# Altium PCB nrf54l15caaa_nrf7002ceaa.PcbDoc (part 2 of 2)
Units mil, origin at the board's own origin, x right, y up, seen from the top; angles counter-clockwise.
Board outline 890.45 x 692.95 mil, 6 copper layers (Top Layer, Mid Layer 1, Mid Layer 2, Mid-Layer 3, Mid-Layer 4, Bottom Layer), stack 38.012 mil thick; 75 components, 69 nets, 285 pads, 346 vias.
Unrouted connection lines stored in the file: 4.

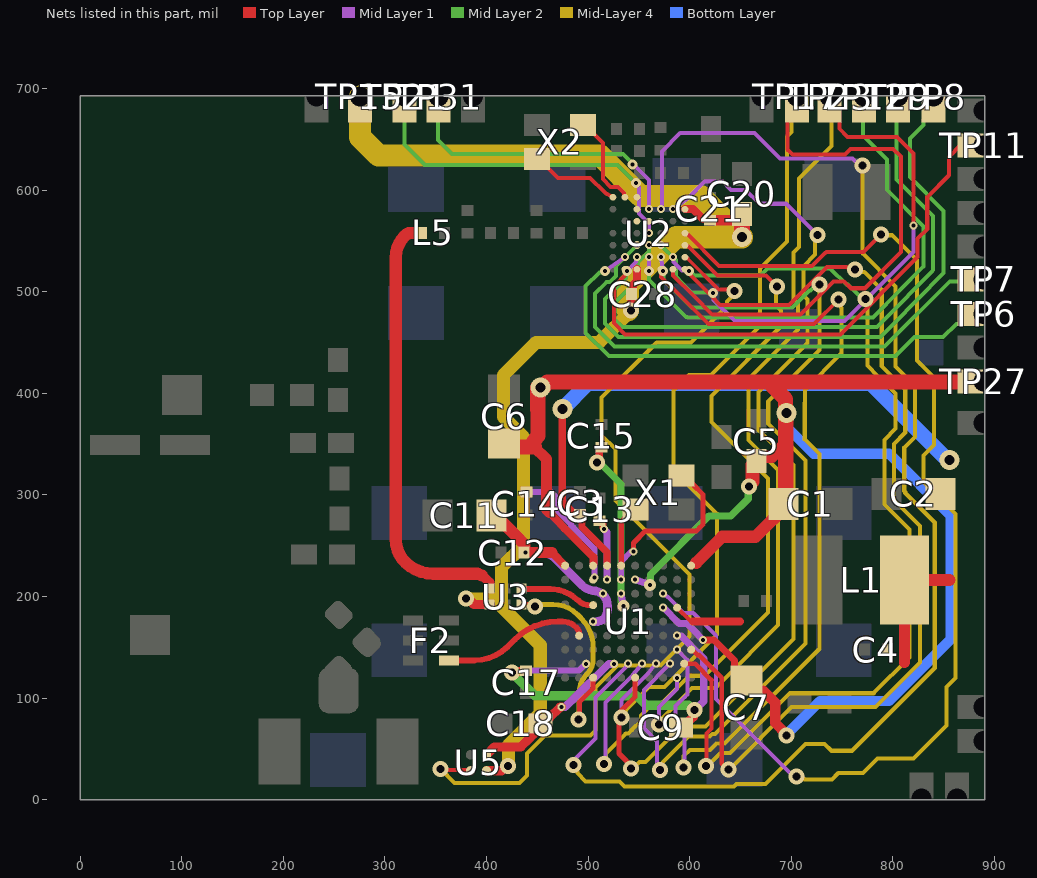
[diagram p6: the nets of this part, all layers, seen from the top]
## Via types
v1: diameter 7.87, hole 3.94, Top Layer to Mid Layer 1, tented top, 93 vias
v2: diameter 19.68, hole 9.84, Top Layer to Bottom Layer, tented both sides, 83 vias
v3: diameter 15.75, hole 7.87, Top Layer to Bottom Layer, tented both sides, 58 vias
v4: diameter 7.87, hole 3.94, Top Layer to Mid Layer 1, tented both sides, 43 vias
v5: diameter 9.84, hole 3.94, Mid Layer 1 to Mid Layer 2, tented top, 22 vias
v6: diameter 15.75, hole 7.87, Mid Layer 1 to Mid Layer 2, tented both sides, 12 vias
v7: diameter 15.75, hole 7.87, Mid Layer 2 to Mid-Layer 4, tented both sides, 11 vias
v8: diameter 11.81, hole 3.94, Top Layer to Mid Layer 1, tented top, 9 vias
v9: diameter 7.87, hole 3.94, Mid Layer 1 to Mid Layer 2, tented top, 6 vias
v10: diameter 11.81, hole 3.94, Mid Layer 1 to Mid Layer 2, 3 vias
v11: diameter 11.81, hole 3.94, Mid Layer 1 to Mid Layer 2, tented both sides, 3 vias
v12: diameter 9.84, hole 3.94, Mid Layer 1 to Mid Layer 2, 2 vias
v13: diameter 11.81, hole 3.94, Top Layer to Mid Layer 1, tented both sides, 1 vias

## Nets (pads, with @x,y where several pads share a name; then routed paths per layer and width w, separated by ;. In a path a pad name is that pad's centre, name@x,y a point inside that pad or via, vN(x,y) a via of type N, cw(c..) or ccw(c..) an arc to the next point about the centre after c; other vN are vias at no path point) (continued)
P1.06/AIN2_BUCKEN: U1.J5 U2.D7 | length 1163.9
  Top Layer w3.94: U2.D7@595.36,557.55 596.11,557.55 597.48,556.17 598.35,556.17 629.06,525.46 647.79,525.46 720.42,525.46 732.61,537.64 733.31,538.2 ccw(c725.54,552) 734.58,539 771.09,539 v3(788.32,556.23)
  Mid Layer 1 w4: v4(573.9,202.78) 574.95,202.78 578.24,199.49 578.53,199.49 594.06,183.96 603.52,183.96 626.09,161.4 626.09,99.08 702.17,23 v3(705,23)
  Mid-Layer 4 w4: v3(705,23) 707.25,20.75 712.47,20.75 713.22,20 719.37,20 ; 719.4,19.98 732.54,19.98 ; 732.57,20 739.9,20 746.24,26.34 770.49,26.34 784.81,40.66 820.29,40.66 852.73,73.1 852.73,110.99 861.73,119.99 861.73,281.14 830.23,312.64 830.23,338.66 840.68,349.11 840.68,415.41 823.73,432.36 823.73,531.18 799.31,555.6 788.95,555.6 v3(788.32,556.23)
P1.07/AIN3/STAT0: U1.B8 U2.E7 | length 827.5
  Top Layer w3.94: U2.E7@595.36,545.73 595.89,545.21 598.17,545.21 627.36,516.02 647.79,516.02 675.13,516.02 v3(686,505.15)
  Mid Layer 1 w4: v3(515.74,35.19) 516.98,36.43 516.98,95.54 543.8,122.36 544.07,122.66 552.51,132.96 v4(553.25,133.86)
  Mid-Layer 4 w4: v3(515.74,35.19) 517.48,36.93 517.48,45.5 537.12,65.14 539.68,65.14 543.42,68.87 543.47,68.87 552,77.4 552,83 564,95 573,95 600.03,122.03 614.9,122.03 676.93,184.06 676.93,315.96 621.32,371.57 621.32,397.32 690,466 690,481.38 684.8,486.59 684.8,503.95 v3(686,505.15)
P1.08_IOEN: U2.F7 U5.B2 | length 889.3
  Top Layer w3.94: U2.F7@595.82,533.4 596.63,533.4 597.09,532.94 597.62,532.94 628.41,502.15 642.88,502.15 v3(644.16,500.87)
  Top Layer w4: v3(355,30.06) 355.81,29.25 383.45,29.25 U5.B2@384.27,28.43
  Mid-Layer 4 w4: v3(355,30.06) 368.65,16.41 432.41,16.41 440,24 440,45.43 457.56,63 502.55,63 507.42,67.87 507.42,110.42 529.18,132.18 571.18,132.18 599.73,160.73 599.73,221.62 527,294.35 527,345 513.33,358.67 513.33,362.72 513.41,362.8 513.41,375.94 513.33,376.02 513.33,395.78 567.61,450.06 601.21,450.06 636.87,485.71 636.87,490.4 642.06,495.59 644.16,497.69 v3(644.16,500.87)
P1.09*: U2.B3
P1.10*: U2.C3
P1.11*: U2.C4
P1.12*: U2.A3
P1.13: TP31.1 U2.B4 | length 296.8
  Mid Layer 1 w3.94: v5(543.8,625) 544.81,625 559.93,609.89 v1(559.93,581.17)
  Mid Layer 2 w3.94: TP31.1@349.85,680.16 349.85,692.95 ; TP31.1@352.38,680.16 352.38,649.41 366.29,635.5 534.31,635.5 543.8,626.01 v5(543.8,625)
P1.14_IRQ: U1.B10 U2.B5 | length 1351.1
  Mid Layer 1 w3.94: v1(571.74,581.17) 572.63,586.51
  Mid Layer 1 w4: v5(485.73,34.18) 486.85,35.3 486.85,39.7 507.48,60.33 507.48,100.54 537.53,130.59 537.53,130.88 539.47,132.81 v4(539.47,133.86) ; 572.63,586.51 572.63,638.17 590.71,656.25 647.79,656.25 663.88,656.25 689.05,631.08 760.33,631.08 767.82,623.59 v10(769.68,623.59)
  Mid Layer 2 w3.94: v10(769.68,623.59) 770.07,623.98 v7(770.34,623.98)
  Mid-Layer 4 w3.94: v5(485.73,34.18) 485.73,30.98 489.4,27.31 489.4,26.24 497.64,18 531,18
  Mid-Layer 4 w4: 531,18 535.86,13.14 643.65,13.14 645.92,15.4 674.72,15.4 714.14,54.82 732.83,54.82 739.47,48.18 759.8,48.18 841.23,129.61 841.23,272.76 812.18,301.81 812.18,302.86 811.23,303.81 811.23,346.53 821.68,356.98 821.68,407.54 802.68,426.54 802.68,505.15 769.96,537.87 769.96,623.6 v7(770.34,623.98)
  other v7: 485.73,34.18
P1.15_SWCTRL1_STAT1: U1.A9 U2.B6 | length 928.8
  Top Layer w4.5: 536.18,91.18 536.48,91.18
  Top Layer w5: v3(542.21,30.66) 542.21,33.57 537.83,37.94 537.83,38.03 530.38,45.48 530.38,85.38 536.18,91.18 546.34,101.34 U1.A9@546.34,120.08
  Mid Layer 1 w3.94: v1@584.55,581.92 599.3,592.98
  Mid Layer 1 w4: 599.3,592.98 614.7,608.39 632.66,608.39 640.86,600.18 654.98,600.18 668.57,586.59 694.82,586.59 v3(725.64,555.77)
  Mid-Layer 4 w3.94: 556.56,37.15 563.45,44.04
  Mid-Layer 4 w4: v3(542.21,30.66) 543.94,30.66 550.42,37.15 556.56,37.15 ; 563.45,44.04 563.56,44.04 591.43,71.91 615.7,71.91 702.13,158.34 702.13,329.36 667.82,363.67 667.82,401.29 716.02,449.5 716.02,492.45 711.87,496.61 711.87,524.86 723.5,536.5 723.5,553.63 v3@727.64,557.77
  other v1: 583.55,581.17
P2.01_SCLK: U1.C1 U2.G7 | length 992.1
  Top Layer w3.94: U2.G7@595.36,522.11 595.36,521.77 607.21,509.92
  Top Layer w4: 607.21,509.92 611.18,505.96 621.55,495.59 630.08,487.06 697.81,487.06 735.23,524.48 754.57,524.48 755.13,523.92 760.54,523.92 v3(762.79,521.67)
  Top Layer w4.7: U1.C1@601.47,147.64 602.33,147.64 607.41,142.56 608.97,142.56 631.6,119.93 631.6,35.55 635.5,31.65 635.55,31.65 637.14,30.06 v4(638,30.06)
  Mid-Layer 4 w4: v7@636.73,29.92 639.09,29.92 700.35,91.18 782.73,91.18 826.81,135.26 826.81,269.21 801.23,294.8 801.23,350.3 812.18,361.25 812.18,403.6 789.03,426.75 789.03,502.24 771.84,519.42 763.42,519.42 v3@763.09,519.75
  other v5: 637.29,30.63
  other v7: 638,29.92
P2.02_MOSI: U1.B2 U2.F6 | length 960
  Top Layer w4: v4(616.52,32.88) 616.52,65.19 621.46,70.13 621.46,101.33 621.46,117.77
  Top Layer w4.7: U1.B2@594.6,133.86 605.37,133.86 621.46,117.77
  Mid Layer 1 w3.94: v1(583.55,533.92) 584.3,533.17 584.3,529.23 592.63,520.91 598.53,520.91 v5(599.3,520.14) ; v5(616.25,33.15) v4(616.52,32.88)
  Mid Layer 2 w3.94: v5(599.3,520.14) 600.88,520.14 604.98,516.04 669.78,516.04 676.74,523 738.16,523 754.16,507 755.96,507 769.97,492.99 v7(773.16,492.99) ; v7(616.3,33.06) v7(616.3,33.06)
  Mid-Layer 4 w4: v7(616.3,33.06) 617.54,33.06 630.26,45.78 631.43,45.78 639.82,45.78 698.84,104.8 781.15,104.8 816.46,140.11 816.46,265.85 791.73,290.58 791.73,354.24 802.68,365.19 802.68,399.62 785.59,416.7 ; v7(773.16,492.99) 775.14,491.02 775.14,427.21 785.59,416.75
P2.04_MISO: U1.B4 U2.F5 | length 905
  Mid Layer 1 w3.94: 554.91,101.33 554.91,107.96 v4(580.82,133.86) ; v1(571.74,533.92) v5(573.71,520.14)
  Mid Layer 1 w4: 554.91,101.33 554.91,70.52 568,57.43 568,35.75 572.3,31.44 v5(572.3,30.48)
  Mid Layer 2 w3.94: v5(572.3,30.48) 572.63,30.15 v7@572.63,29.92 ; v5(573.71,520.14) 574.44,519.41 574.44,511.67 590.53,495.59 600.68,485.43 601.84,484.28 701.11,484.28 718.06,501.23 719.04,501.23 724.8,507 v7(728,507)
  Mid-Layer 4 w4: v7@571.09,30.01 573.25,32.16 573.25,36.39 598.95,62.09 619.6,62.09 622.29,64.78 624.93,64.78 714,153.85 714,333.66 677.32,370.34 677.32,392.15 728,442.82 v7(728,507)
  other v7: 571,29
P2.05_CS: U1.C3 U2.G5 | length 894.9
  Top Layer w3.94: U2.G5@571.74,522.11 571.77,514.59 590.78,495.59 618.37,468 722.55,468 v3(746.73,492.18)
  Mid Layer 1 w3.94: v4(587.7,147.64) 597.63,137.72 597.63,103.63 595.33,101.33 586.27,92.27 586.27,76.34 594.98,67.63 v3@594.98,31.62
  Mid-Layer 4 w4: v3(594,31.62) 594.16,31.78 594.16,43.09 600.09,49.02 620.06,49.02 626.32,55.28 634.42,55.28 727.73,148.59 727.73,340.27 713.3,354.7 713.3,390.44 713.44,390.59 713.44,403.44 749.65,439.65 749.65,483.96 748.98,484.63 748.98,489.93 v3(746.73,492.18)
P2.06: TP12.1 U2.F4 | length 520.7
  Mid Layer 1 w3.94: v5(559.93,520.14) v1(559.93,533.92)
  Mid Layer 2 w3.94: v5(559.93,520.14) 559.93,511.45 575.79,495.59 575.84,495.59 596.18,475.25 597.52,475.25 597.93,474.84 645.73,474.84 ccw(c647.79,500.03) 649.86,474.84 780.58,474.84 781.75,476.02 830,525.05 830,564.35 794,600.35 794,630.34 770.46,653.88 770.46,690.98 TP12.1@771.46,691.98
P2.07: TP9.1 U2.E4 | length 613.2
  Mid Layer 2 w3.94: v1(559.93,545.73) 559.79,545.59 559.79,539.69 549.1,529 549.1,512.15 526.03,489.08 526.03,472.78 532.25,466.56 533.4,465.41 645.37,465.41 ccw(c647.79,500.03) 650.21,465.41 784.49,465.41 791.19,472.11 838.31,519.99 839.44,521.14 839.44,574.56 803.44,610.56 803.44,690.33 TP9.1@805.08,691.98
  other v9: 559.93,545.73
P2.08: TP21.1 U2.D4 | length 345.5
  Mid Layer 1 w3.94: v5(547.38,607) 547.38,605.4 549.99,602.8 549.99,577.19 559.79,567.39 559.79,557.69 v1(559.93,557.55)
  Mid Layer 2 w3.94: TP21.1@319.33,691.98 319.33,644.87 339.45,624.75 477.52,624.75 528.74,624.75 546.49,607 v5(547.38,607)
P2.09: TP8.1 U2.F3 | length 640.7
  Mid Layer 1 w3.94: v5(538.27,520.14) 547.36,529.23 547.36,533.17 v1(548.12,533.92)
  Mid Layer 2 w3.94: v5(538.27,520.14) 537.29,519.16 537.29,513.69 516.59,492.99 516.59,468.87 530.1,455.36 779.82,455.36 781.31,455.36 787.79,455.36 800.61,468.18 ; 800.63,468.21 848.87,517.23 850,518.37 850,579.58 816.89,612.69 816.89,650.89 830.16,664.16 830.16,668.35 839.44,677.63 840,677.63 TP8.1@840,691.98
P2.10: TP11.1 U2.G2 | length 544.1
  Top Layer w3.94: 525.48,495.59 525.48,505.38 536.24,516.14 U2.G2@536.31,522.11 U2.G2@536.31,522.11
  Top Layer w4: 525.48,495.59 525.48,469.01 536.49,458 748.25,458 824.39,534.14 824.39,552.35 833.86,561.82 833.86,593.26 855.22,614.62 855.22,621.02 855.28,621.08 855.28,632.72 867.27,644.71 890.45,644.71
PALDO: C11.2 C12.2 U1.E16 U1.J14 U1.L20 | length 225.8
  Top Layer w7.87: 464.47,243.3 U1.L20@477.42,230.34
  Top Layer w11: 431.7,256.75 431.7,257.04 ; C12.2@437.29,244.35 v4(438.43,243.21) ; C12.2@438.43,243.3 464.47,243.3
  Top Layer w12: C11.2@404.83,279.88 408.85,279.88 431.7,257.04 ; 431.7,256.75 437.29,251.15 C12.2@437.29,244.35
  Mid Layer 1 w8.5: v4(438.43,243.21) 438.52,243.3 454.49,243.3 cw(c454.49,225.52) 467.07,238.09 479.05,226.1 493.84,211.31 ; 493.84,211.21 ccw(c507.48,224.85) 507.48,205.57 ; v4(504.99,175.21) 506.43,175.21 ccw(c506.43,193.21) 515.1,177.43 ccw(c505.3,187.24) 519.16,187.24 519.16,190.8 ccw(c503.26,190.8) v4@514.5,202.04 ; 507.48,205.47 cw(c503.93,189.97) v4@514.5,201.84
  other v4: 514.73,202.78
PWRIOVDD: C9.1 C17.2 U1.B17 U1.D3 | length 390.9
  Top Layer w6: C17.2@438.71,127.12 C17.2@438.97,126.87
  Top Layer w9: v3(425,125) 426.05,126.05 437.64,126.05 C17.2@438.71,127.12 ; C9.1@591.42,71.18 593.39,71.18 603.71,81.49 603.71,87.21 v3(605,88.5)
  Mid Layer 1 w6: 433.39,127 491.03,127 497.22,133.18 v4@497.72,133.18
  Mid Layer 1 w7: v4(587.69,161.43) 587.86,161.26 591.67,161.26 600.85,152.08 600.85,151.94 613.91,138.88 613.91,96.91 v3@605.25,88.25
  Mid Layer 2 w9: v3(425,125) 426.44,123.58 447.74,102.28 547.82,102.28 557.1,93 598.67,93 603.17,88.5 v3(605,88.5)
  other v4: 498.08,133.54
QSPI_DIO2_P2.03: TP23.1 U1.A3 U2.E5 | length 1332.2
  Top Layer w3.94: TP23.1@737.83,679.18 TP23.1@737.83,691.98 747.26,682.55 747.26,660.4 755.39,652.27 804.24,652.27 820.28,636.23 v1@820.28,565.11
  Mid Layer 1 w4: v7(570,74) 570,91.46 587.69,109.15 v4(587.69,120) ; v5(622.95,498.66) 623.57,498.04 623.57,495.59 623.57,491.84 644.42,471 752.18,471 820.18,539 v1(820.18,565.01)
  Mid Layer 2 w3.94: v9@571.81,545.66 586.5,530.97 586.5,516.36 586.42,514.88 586.42,514.81 593.07,508.16
  Mid Layer 2 w4: 593.04,508.14 602.03,499.15 622.46,499.15 v5(622.95,498.66)
  Mid-Layer 4 w3.94: v7(570,74) 570,77.2 574.07,81.26 574.07,81.55 593.85,101.33 602.52,110 625.27,110 631.69,116.42 687,171.73 687,324.73 657.92,353.81 657.92,414.2 706.55,462.84 706.55,488.53 702.4,492.69 702.4,538.76 707.55,543.91 707.55,611.55 739.5,643.5 739.5,690.31 TP23.1@737.83,691.98
  other v1: 571.74,545.73
  other v5: 570,74
  other v9: 571.74,545.73
QSPI_DIO3_P2.00: TP17.1 U1.B6 U2.G6 | length 1356.2
  Top Layer w3.94: U2.G6@583.55,522.11 U2.G6@583.55,522.11 583.62,516.14 604.17,495.59
  Top Layer w4: 604.17,495.59 622.2,477.56 709.11,477.56 741.77,510.22 751.8,510.22 758.61,503.41 772.41,503.41 807.92,538.92 807.92,632.96 800.28,640.6 758.29,640.6 752.69,635 701.11,635 696.37,639.74 696.37,682.83 TP17.1@705.52,691.98
  Mid Layer 1 w4: v5(532.97,80.65) 532.97,98.09 558.44,123.56 v4(566.82,134.23)
  Mid Layer 2 w3.94: v5@530.12,80.65 v5(532.97,80.65)
  Mid-Layer 4 w4: v5(532.97,80.65) 532.97,83.82 537.14,88 537.14,88.09 560.04,110.99 575.16,110.99 626.96,162.79 626.96,281.07 584,324.03 584,402.72 599.18,417.89 620.89,417.89 667.59,464.59 667.59,477.59 669.28,479.28 669.28,522.66 696,549.38 696,653 700.35,657.35 700.35,686.81 TP17.1@705.52,691.98
  other v7: 532.97,81
RF: L5.2 U3.3 | length 433.1
  Top Layer w9.5: 395.57,220.68 cw(c395.57,219.02) 396.75,220.2 403,213.95 U3.3@403.3,212.6 ; U3.3@403,212.6 403.16,212.44 U3.3@403.16,212.26
  Top Layer w12: L5.2@335,557.92 326.34,557.92 ccw(c326.34,548.57) 319.73,555.18 ccw(c341.46,533.45) 310.73,533.45 310.73,256.22 ccw(c342.41,256.22) 320.01,233.82 ccw(c347.42,261.24) 347.42,222.47 391.27,222.47 395.57,220.68
RFVDD: C13.2 U1.K13 | length 59.7
  Top Layer w7: C13.2@512.44,273.58 513.03,273.58 514.84,271.76 514.84,267.4 v1(515.84,266.41)
  Mid Layer 1 w7: v1@516,266.24 516,266 518.73,263.27 v4(518.73,216.64)
SW_CTRL0: U1.A16 U3.6 | length 214.6
  Top Layer w5: U3.6@434.66,192.13 443.6,192.13 cw(c443.6,184.87) v3@448.73,190 ; v3@491.33,80.65 491.55,80.87 491.55,96.31 504.99,109.74 U1.A16@504.99,120.08
  Mid Layer 1 w5: v3@490.55,80.65 v3@491.33,80.65
  Mid-Layer 4 w5: v3@448.73,192.18 465.6,192.18 cw(c465.6,158.26) 489.58,182.25 ; 489.59,182.24 493.08,178.75 ; v3@491.21,79.95 491.21,105.32 cw(c516.68,105.32) 498.65,123.31 ccw(c483.41,138.59) 502.46,128.45 ccw(c483.41,138.59) 504.99,138.59 504.99,150 ccw(c464.33,150) 502.46,164.12 ccw(c464.33,150) 493.1,178.73
  other v3: 490.64,79.02 447.73,190
SWDCLK: TP7.1 U2.E3 | length 517.4
  Mid Layer 2 w3.94: v9(548.12,545.73) 527.45,525.07 527.45,515.66 521.11,509.32 518.13,509.32 507.03,498.21 507.03,465.09 526.19,445.93 785.71,445.93 791.7,445.93 855.99,510.22 890.45,510.22
  other v1: 548.12,545.73
SWDIO: TP6.1 U2.F2 | length 513.9
  Mid Layer 1 w3.94: v5(516.62,520.14) 536.21,533.85 v1(536.31,533.92)
  Mid Layer 2 w3.94: v5(516.62,520.14) 515.49,519.01 511.13,519.01 497.54,505.43 497.54,459.49 520.54,436.49 802.49,436.49 821.36,455.36 849.36,455.36 862.45,468.45 865.83,468.45 871.73,474.36 871.73,475.29 890.18,475.29
SXLDO: C14.2 U1.K16 | length 124.2
  Mid Layer 1 w6: v4(439.16,302.74) 463.38,302.74 467.48,298.64 ; 467.48,287.08 483.33,271.22 483.33,269.88 485.56,267.65 506.22,247 v4@506.22,220.48 ; 467.58,287.08 467.58,298.64
  other v4: 506.43,218.5
TXRF0: U1.G16 U3.1 | length 74.7
  Top Layer w5.75: 466.89,207.08 cw(c463.01,170.65) 475.42,205.12 cw(c463.01,170.65) 478.7,203.76 482.1,202.14 cw(c477.42,192.26) 484.12,200.9 ; 484.16,200.88 490.52,195.94 ccw(c501.31,206.72) 493.54,193.6 ccw(c501.31,206.72) 497.91,191.86 ccw(c501.31,206.72) 501.31,191.47 U1.G16@504.99,191.47
  Top Layer w5.76: U3.1@434.66,207.87 435.07,207.46 463.14,207.46 466.89,207.08
TXRF1: F2.1 U1.D18 | length 148.8
  Top Layer w5.76: F2.1@360.42,137.4 F2.1@363.03,137.4 ; F2.1@363.03,137.18 388.08,137.18 ccw(c388.08,183.75) 421.01,150.82 428.02,157.83 cw(c470.36,115.49) 470.36,175.37 474.64,175.37 cw(c474.6,156.17) 488.18,169.75 488.55,169.37 ; 488.57,169.35 cw(c481.57,162.39) U1.D18@491.44,162.39
VBAT: C1.2 C5.1 C6.2 C7.2 TP27.1 U1.F5 U1.K9 U1.L1 U1.L16 | length 1860.4
  Top Layer w7: v1(613.29,157.09) 623.98,157.09 643.99,137.07 643.99,127.12 C7.2@649.72,121.39
  Top Layer w7.87: 461.95,282.79 476.26,267.65 ; 477.24,266.66 505.19,238.72 U1.L16@505.19,232.06
  Top Layer w10: C7.2@652.69,122.44 656.21,118.92 656.21,116.87 665.44,107.64 672.03,107.64 684.24,95.43 684.24,75.48 695.15,64.56 v3(695.15,63.01)
  Top Layer w11: 446.95,347.25 458.94,335.26 458.94,290.34 458.94,285.97 461.95,282.79
  Top Layer w12: 606.48,233.17 632.14,258.83 664.84,258.83 C1.2@681.99,275.98 ; v3(658.15,308.43) 658.15,309.45 v3@661.8,313.1 ; C5.1@661.8,329.33 C5.1@665.64,333.17 ; C5.1@667.99,337.48 680.92,337.48 694.5,351.06
  Top Layer w12.5: C1.2@681.97,275.98 C1.2@691.24,284.24
  Top Layer w14: v3@661.8,313.1 C5.1@661.8,329.33
  Top Layer w15: C6.2@417.43,345.61 419.07,347.25 446.95,347.25 ; 445.18,350.18 450.59,358.26 ; v2@450.58,405.68 450.77,358.26 ; v2(453.03,405.69) 454.3,405.69 459.8,411.18 677.33,411.18 694.26,394.25 v2@694.26,381.47 ; v2@453.93,406.58 v2@457.24,406.58 ; 660,411.18 TP27.1@886.57,411.18 ; C1.2@692.24,291.22 694.5,293.49 694.5,351.06 v2@694.5,379.92
  Mid Layer 1 w6.8: v4@574.18,188.99 589.71,173.46 597.19,173.46 603.22,167.43 ; 603.22,167.39 613.29,157.32 v1(613.29,157.09)
  Mid Layer 1 w7: v4@547.38,216.2 v11(561.01,211.47)
  Mid Layer 2 w7: v11(561.01,211.47) 561.37,211.83 561.37,221.82 618.96,279.41 640.77,279.41 657.61,296.25 v3@657.61,307.39
  Bottom Layer w10: v3(695.15,63.01) 695.15,64.06 728.12,97.03 796.1,97.03 856.59,157.52 856.59,280.14 796.28,340.45 721.91,340.45 696.04,366.32 v2@696.04,379.69
  other v2: 695.15,380.57
  other v4: 573.9,188.99 546.34,216.56
VDD_BUCK: C2.2 C3.2 C4.2 L1.2 U1.F3 U1.L13 | length 785.3
  Top Layer w4.2: U1.F3@587.69,188.99 600.27,176.41 602.32,176.41
  Top Layer w7: v2(474.64,384.48) 474.64,293.5 486.44,281.7 490.24,281.7 C3.2@492.06,279.88 ; C3.2@494.07,278.15 494.07,268.23 518.77,243.53 U1.L13@518.77,230.34
  Top Layer w8: 603.34,175.39 649.39,175.39
  Top Layer w10.98: 811.52,134.92 L1.2@811.52,211.97
  Top Layer w12: L1.2@808.74,216.22 L1.2@811.52,216.22 855.83,216.22
  Bottom Layer w15: v2(474.64,384.48) 500.16,410 778.15,410 851.34,336.81 852.32,336.81 854.66,334.47 v2(855.93,334.47)
VDD_nRF: C20.2 C21.1 C28.1 TP15.1 U2.B7 U2.G3 U3.4 U5.A2 | length 1387.6
  Top Layer w7.87: v3(542.25,481.36) 542.53,481.64 542.53,497.23 C28.1@542.8,497.51 ; C28.1@544.18,497.51 544.18,506.67 548.12,510.61 U2.G3@548.12,522.11 ; U2.B7@595.36,581.54 603.23,581.54 613.08,571.7 C21.1@618.59,571.7
  Top Layer w9: v3(380,198) 381.83,198 387.7,192.13 U3.4@403.16,192.13 ; U5.A2@400.02,28.43 400.07,28.48 414.74,28.48
  Top Layer w10.63: C21.1@619.97,570.32 C20.2@645.16,570.32
  Top Layer w15.75: v2(651.46,553.99) C20.2@651.46,576.62
  Mid-Layer 4 w10: v3@381.1,198.9 414.77,198.9
  Mid-Layer 4 w13: v3(421.14,33.06) 421.67,33.58 421.67,53.67 453.03,85.04 453.03,151.96 414.77,190.23 414.77,198.9 414.77,228.78 436.52,250.52 436.52,356.92 416.73,376.71 416.73,417.89 448.9,450.06 510.94,450.06 v3(542.25,481.36)
  Mid-Layer 4 w15: 275.46,656.52 275.61,656.38 275.61,652.14
  Mid-Layer 4 w22: 275.46,656.52 TP15.1@275.46,691.98 ; 275.61,652.14 293.75,634 511.98,634 551.8,594.18 610.89,594.18 651.46,553.61 586.71,553.61 539,505.9 v3@539,481.71
VDDIO: C18.2 U1.B12 U5.A1 | length 157.2
  Top Layer w7.87: U5.A1@400.02,44.18 U5.A1@400.28,44.44
  Top Layer w9: U5.A1@400.13,44.23 407.91,52 433.79,52 442.34,60.55 446.1,64.32 446.1,69.84 451.45,75.18 C18.2@453.41,75.18 ; C18.2@460.35,80.53 461.92,80.53 472.58,91.18 v1(473.9,91.18)
  Mid Layer 1 w7.87: v1(473.9,91.18) 477.39,91.18 483.87,97.66 484.3,97.66 520.42,133.79 v4(525.68,133.79)
XC1: U2.A1 X2.1 | length 89.8
  Top Layer w3.94: X2.1@449.69,630.76 458.55,621.9 460.55,621.9 470.3,612.15 502.09,612.15 515.99,598.25 516.6,597.63 ccw(c522.17,603.2) 518.42,596.28 522.41,594.11 U2.A1@524.49,592.98
XC2: U2.A2 X2.3 | length 91.4
  Top Layer w3.94: X2.3@494.97,664.22 X2.3@503.83,655.36 ; X2.3@505.79,655.36 514.65,646.5 514.65,610.72 522.17,603.2 529.42,603.2 535.55,597.06 535.55,594.11 U2.A2@536.31,593.36
XOLDO: C15.2 U1.J11 | length 180
  Top Layer w7.5: v3@508.94,331 508.94,333.23 510.87,335.17 510.87,345.36 512.44,346.93 C15.2@513.03,346.93
  Mid Layer 1 w7: v4(532.56,202.78) v11(534.76,190.57)
  Mid Layer 2 w7: v3@512.15,330.83 532.34,310.64 532.34,194.15 534.76,191.73 v11(534.76,190.57)
  other v3: 508.94,331.8
XON: U1.L11 X1.1 | length 60.3
  Top Layer w5.5: U1.L11@532.56,230.34 532.56,273.46 X1.1@544.69,285.59
XOP: U1.K11 X1.3 | length 177.1
  Top Layer w5: v4(544.71,244.2) 544.71,252.75 556.55,264.6 606.78,264.6 609.83,267.65 613.29,271.11 613.29,300.24 602.8,310.73 600.26,310.73 X1.3@591.93,319.06
  Mid Layer 1 w5.5: v4(532.65,216.62) 532.65,234.72 541.87,243.94 544.45,243.94 v4(544.71,244.2)
pads on no net: A1.1 A1.2 A1.3 U1.C20 U1.K5 U1.K7 U1.L5 U1.L7

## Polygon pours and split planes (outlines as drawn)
GND on Top Layer "g0.01" (solid, remove dead copper, pour order 1145): -46.27,730.33 909.73,730.33 909.73,421.38 378.26,421.38 378.26,-14.82 -46.27,-14.82
GND on Top Layer "Top_Layer-GND" (solid, remove dead copper, pour order 1024): 361.18,-14.82 361.18,432.45 890.53,432.45 890.53,-14.82
VDD_BUCK on Top Layer "NONET_L-01_P-001" (solid, pour order 1148): 869.18,346.41 877.47,338.12 877.47,138.48 852.45,113.46 700.77,113.46 645.71,168.52 627.85,168.52 624.54,171.82 624.54,182.98 653.14,183.08 704.05,132.18 779.54,132.18 787.31,139.95 787.31,258.46 813.32,284.47 813.32,336.12 823.61,346.41
GND on Top Layer "NONET_L-01_P-001" (solid, pour order 1150): 667.38,202.89 661.09,209.18 594.34,209.18 594.34,226.01 691.53,226.01 693.85,223.69 693.85,168.18 695.51,166.52 755.83,166.52 758.97,169.74 758.97,263.4 755.48,266.89 733.5,266.89 725.54,274.84 725.54,302.65 769.24,346.34 816.46,346.34 820.64,342.17 820.64,279.54 807.98,266.89 784.28,266.89 779.16,261.77 779.16,173.37 782.43,170.1 782.43,141.97 778.15,137.8 704.97,137.8 667.38,175.39
GND on Mid Layer 1 "Mid_Layer_1-GND" (solid, remove dead copper, pour order 1149): -6.8,733.45 -6.8,-28.82 919.65,-28.82 919.65,733.45
GND on Mid Layer 1 "GND_L02_P1032" (solid, pour order 1032): 647.41,225.39 647.57,164.61 694.37,117.8 847.54,117.8 858.69,128.95 858.69,307.22 819.11,346.8 741.82,346.8 647.41,252.39
GND on Mid Layer 2 "Mid_Layer_2-GND" (solid, remove dead copper, pour order 1151): -3.04,732.18 -3.04,-25.82 921.96,-25.82 921.96,732.18
GND on Mid-Layer 3 "Mid_Layer_3-GND" (solid, remove dead copper, pour order 1004): -12.27,737.54 -12.27,-25.82 912.73,-25.82 912.73,737.54
GND on Mid-Layer 4 "Mid_Layer_4-GND" (solid, remove dead copper, pour order 1002): -9.09,736.28 -9.09,-12.82 924.73,-12.82 924.73,736.28
GND on Bottom Layer "Bottom_Layer-GND" (solid, remove dead copper, pour order 1001): -45.43,743.3 -45.43,-20.82 897.02,-20.82 897.02,743.3

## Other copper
Top Layer:
  rectangle net GND: 846,374 867,379.81
  rectangle net NetZ1_1: 206.48,383.7 229.98,412.7
  rectangle net NetZ2_1: 241.33,206.42 270.33,288.46
  rectangle net NetZ1_1: 241.33,304.21 270.33,370.26
  rectangle net VBAT: 672.14,326.18 691.24,337.03
  rectangle net NetA1_4: 80.54,377.88 196.83,418.04
  rectangle net GND: 556.34,172.26 563.93,206.12
  rectangle net GND: 501.25,157.63 520.1,165.2
  rectangle net GND: 514.94,143.9 550.28,192.8
  rectangle net GND: 555.61,143.9 577.6,179
  region net GND: 323.3,268.7 323.3,257.13 ccw(c341.02,257.13) 328.49,244.6 338.43,244.6 338.5,244.67 338.63,244.67 338.63,315.52 324.3,315.52 323.4,315.5 323.3,315.4
  pour cut-out: 231.6,140.28 cw(c236.41,135.47) 236.41,142.26 274.31,142.26 cw(c274.27,132.86) 280.95,139.48 cw(c269.7,128.28) 285.57,128.28 285.57,87 cw(c279.89,86.92) 283.95,82.94 cw(c280.44,85.83) 283.65,82.61 cw(c268.92,97.33) 268.92,76.51 239.55,76.51 cw(c239.55,87.37) 231.86,79.69 229.25,82.31 cw(c243.01,96.07) 223.55,96.07 223.55,126.95 cw(c238.48,126.95) 227.92,137.51 228.38,137.97 cw(c236.92,129.44)
  region net NetZ1_1: 228.12,412.7 248.21,412.7 cw(c248.22,386.61) 266.66,405.06 cw(c257.9,396.28) 270.31,396.29 270.31,377.43 270.32,370.05 241.33,370.05 241.33,378.56 ccw(c236.01,378.57) 239.77,382.33 ccw(c236.46,379.03) 236.46,383.7 228.12,383.7
  pour cut-out: 616.97,226.87 612.73,222.63 cw(c607.88,227.48) 607.88,220.62 605.41,220.62 605.27,220.76 605.27,222.47 606.98,222.47 ccw(c606.98,234.86) 616.54,226.97
  pour cut-out: 486.69,298.01 497.96,298.01 cw(c497.96,295.03) 500.07,297.14 505.53,291.67 517.34,291.67 517.34,279.86 505.53,279.86 486.69,279.88
  pour cut-out: 379,145 399.91,145 425.76,170.85 438,170.85 438,185.06 423.85,185.06 408.16,169.37 379,169.37
  pour cut-out: 779.1,427.5 835.6,427.5 835.6,421.7 835,421.1 834.4,421.7 778,421.7 778,427.5
  pour cut-out: 439.5,420.8 506.43,420.8 506.43,428.5 442.6,428.5 442.6,424.1 439.5,421
  pour cut-out: 347.33,110.55 415.36,110.55 418.91,114.1 418.91,208.4 415.33,211.97 347.33,211.97
  pour cut-out: 513.67,680.95 429.74,680.95 429.74,614.03 513.67,614.02
  pour cut-out: 204,701.99 405.71,701.99 405.71,654.99 204,654.99
  pour cut-out: 236.06,181.65 278.76,181.52 278.76,139.43 236.06,139.09
  pour cut-out: 408.48,234.01 408,233.53 408,224.08 465.33,224.08 465.33,234.28 408.42,234.28
  pour cut-out: 699.58,636.31 809.02,636.31 809.02,561.18 699.58,561.18
  pour cut-out: 853,352.18 853,704.18 895,704.18 895,352.18
  pour cut-out: 652.69,701.99 898.05,701.99 898.05,659.3 652.69,659.3
  pour cut-out: 536.31,557.55 515.74,557.55 515.74,581.17 536.31,581.17
  pour cut-out: 655.48,524.66 655.28,524.66 655.28,540.16 641.78,540.16 641.08,540.86 641.08,529.46 650.08,529.46 655.18,524.36
  pour cut-out: 4.58,729.96 204.23,729.96 204.23,-21.24 4.58,-21.24
  region net NetF2_6: 319.32,161.6 283.18,169.44 283.18,140.31 319.45,152.11
  pour cut-out: 236.33,305.44 275.41,305.33 275.41,288.91 236.33,288.61
  pour cut-out: 638.94,102.64 638.94,79.02 670.44,79.02 670.44,102.64
  pour cut-out: 691.58,225.98 693.88,223.68 693.78,223.58 693.78,168.18 693.88,168.18 695.58,166.48 695.68,166.58 755.82,166.58 758.98,169.75 758.98,263.38 758.88,263.38 755.38,266.88 731.28,266.88 731.18,266.78 731.18,259.92 750.3,259.92 750.3,172.52 701.87,172.52 701.87,232.11 628.08,232.11 628.08,226.08 630.97,226.08 631.07,225.98
  pour cut-out: 667.38,188.32 654.63,188.32 654.63,180.46 702.91,132.18 779.54,132.18 788,140.64 788,259.43 789.01,260.44 814.08,260.31 831.99,278.22 831.99,342.34 813.6,360.73 755.79,360.73 707,311.94 707,294.57 663.58,251.15 650.75,251.15 649.97,250.37 649.97,248.63 650.88,247.72 696.9,247.72 717.33,247.72 727.5,257.89 733.98,257.89 733.98,266.41 726.62,273.77 726.62,303.72 769.31,346.41 816.39,346.41 820.18,342.63 820.18,279.08 807.99,266.89 782.42,266.89 779.16,263.63 779.16,173.37 781.45,171.08 781.45,143.1 777.05,138.7 704.83,138.7 667.38,176.15
  pour cut-out: 598.18,215.18 598.18,218.84 599.54,220.2 605.52,220.2 606.78,221.46 606.78,223.8 592.41,223.8 591.81,223.21 591.81,215.23 597.73,215.23
  region net BUCKOUT: 636.53,246.18 648.64,246.18 651.01,243.81 651.01,233.85 649.34,232.18 627.71,232.18 627.44,232.45 627.44,237.11
  pour cut-out: 517.34,298.39 517.34,291.67 520.37,291.67 520.1,291.94 520.1,298.39
  pour cut-out: 869.18,346.41 877.47,338.12 877.47,138.58 852.42,113.54 700.84,113.54 700.77,113.46 645.71,168.52 621.5,168.52 617.5,164.52 619.46,162.56 619.46,156.04 643.12,156.04 699.66,99.5 862.76,99.5 890.53,127.27 890.53,353.42 883.22,360.73 811.52,360.73 811.52,346.41
  region net VBAT: 599.32,235.99 597.64,234.31 597.64,228.61 599.68,226.57 608.32,226.57 611.79,230.04 603.33,238.5 600.83,235.99
  pour cut-out: 557.34,244.2 571.35,258.21 614.68,258.21 615.3,258.83 617.5,256.63 589.39,228.52 557.34,228.52
  pour cut-out: 524.49,367.77 524.49,272.08 609.7,272.08 609.7,368.2
  pour cut-out: 613.89,226.01 613.89,234.09 630.8,251 654.54,251 656.44,249.11 655.01,247.67 637.21,247.67 631.07,241.53 631.07,226.01
  pour cut-out: 662.52,182.68 667.38,187.54 667.38,202.87 661.07,209.23 596.97,209.23 596.97,185.65 598.25,185.65 601.22,182.68
  pour cut-out: 810.63,359.73 845.31,359.73 851.87,353.17 827.27,328.57 824.34,328.57 824.34,340.4 810.63,355.14
  pour cut-out: 667.38,188.32 654.63,188.32 654.63,180.46 702.91,132.18 779.54,132.18 788,140.64 788,259.43 789.01,260.44 814.08,260.31 831.99,278.22 831.99,342.34 813.6,360.73 755.79,360.73 707,311.94 707,294.57 663.58,251.15 650.75,251.15 649.97,250.37 649.97,248.63 650.88,247.72 696.9,247.72 717.33,247.72 727.5,257.89 733.98,257.89 733.98,266.41 726.62,273.77 726.62,303.72 769.31,346.41 816.39,346.41 820.18,342.63 820.18,279.08 807.99,266.89 782.42,266.89 779.16,263.63 779.16,173.37 781.45,171.08 781.45,143.1 777.05,138.7 704.83,138.7 667.38,176.15
  pour cut-out: 829.53,285.08 845.69,268.92 819.64,268.92 819.64,275.2
  pour cut-out: 440.74,388.58 440.74,364.96 393.52,364.96 393.52,388.58
  pour cut-out: 438.6,196.63 464.37,196.63 464.37,186.87 455.49,177.99 438.41,177.99
  pour cut-out: 411.65,154.82 414.5,157.79 470.17,157.79 476.64,151.32 476.64,128.87 505.09,100.41 505.09,71.81 459.43,71.81 411.65,119.59
  pour cut-out: 366.45,303.93 390.07,303.93 390.07,256.13 366.45,256.13
Mid Layer 1:
  pour cut-out: 349.99,234.77 cw(c349.89,267.03) 327.15,244.14 cw(c337.66,252.87) 325.27,247.12 cw(c330.74,252.6) 323.3,250.46 323.3,531.42 cw(c337.41,534.35) 327.22,544.54 cw(c330.11,541.65) 330.11,545.73 351.4,545.73 351.4,569.73 323,569.73 ccw(c322.99,555.87) 313.19,565.67 307.52,560 ccw(c328.7,538.81) 302.52,553.38 ccw(c313.43,542.47) 298,542.47 298,256 ccw(c341.45,256) 310.73,225.27 313,223 ccw(c344.38,254.38) 344.38,210 356.74,210 387.56,210 cw(c387.57,198.08) 396,206.5 cw(c390.01,200.51) 398.1,203.02 399.16,202.04 407.23,202.04 ccw(c407.23,204.55) 409,202.78 410.78,204.56 ccw(c409.48,205.88) 411.33,205.89 ccw(c405.27,208.8) 411.95,208.01 ccw(c385.46,208.08) 404.22,226.78 399,232 ccw(c392.32,225.33) 392.32,234.77
  pour cut-out: 230.41,140.39 cw(c235.22,135.59) 235.22,142.38 273.12,142.38 cw(c273.08,132.97) 279.76,139.6 cw(c268.5,128.4) 284.38,128.4 284.38,87.1 cw(c278.69,87.03) 282.76,83.06 cw(c279.1,86.08) 282.46,82.72 cw(c267.73,97.45) 267.73,76.62 238.36,76.62 cw(c238.36,87.49) 230.67,79.81 228.06,82.42 cw(c241.82,96.19) 222.36,96.19 222.36,127.07 cw(c237.29,127.07) 226.73,137.62 227.19,138.09 cw(c235.73,129.56)
  pour cut-out: 222.7,418.18 222.73,422.98 258.73,422.98 cw(c258.71,404.89) 271.52,417.66 cw(c268.93,411.42) 273.73,416.18 cw(c273.24,415.66) 273.78,416.13 cw(c265.01,407.47) 277.33,407.39 277.33,175.21 232.93,175.21 232.93,370.46 ccw(c227.82,370.46) 231.43,374.08 ccw(c226.36,369.02) 226.36,376.18 222.7,376.18
  pour cut-out: 573.8,227.44 cw(c567.18,234.04) 567.16,224.69 564.64,224.69 560.86,224.69 ccw(c560.85,219.49) 557.37,223.36 556.87,222.86 ccw(c563.37,216.39) 554.2,216.33 554.2,209.66 554.17,209.63 576.19,209.63 576.19,219.03 624.06,266.42 661.44,266.42 741.82,346.8 819.18,346.8 858.69,307.29 858.69,128.49 848,117.8 695.03,117.8 631.33,181.5 620.84,171.01 686.27,105.58 856.36,105.58 873.18,122.41 873.18,339.18 854.84,357.53 735.37,357.53 656.24,278.4 624.76,278.4
  pour cut-out: 553,588.43 523,588.43 523,577.19 540.06,577.19 542.25,575 542.25,565.01 553,565.01
  region net GND: 856,358 844,358 839.89,362.11 840,373 843,376 864,376 882,358 882,343 879,340 874,340
  pour cut-out: 205,701.99 405.71,701.99 405.71,654.99 205,654.99
  pour cut-out: 848,347.18 848,702.18 895,702.18 895,347.18
  pour cut-out: 652.69,701.99 898.05,701.99 898.05,654.99 652.69,654.99
  pour cut-out: 310.11,135.18 233.35,135.18 233.35,177.31 310.11,177.31
  pour cut-out: 278.33,180.58 278.33,172.18 278.13,171.98 278.33,171.78 287.13,171.78
  pour cut-out: 288.78,135.58 280.38,135.58 280.18,135.78 279.98,135.58 279.98,126.78
  pour cut-out: 195.82,418.18 277,418.18 277,376.18 195.82,376.18
  region net BUCKOUT: 584.07,225.93 589.57,225.93 593.01,229.37 593.01,235.28 596.64,238.91 606.64,238.91 609.06,236.49 609.06,232.46 589.4,212.8 584.84,212.8 582.83,214.81 582.83,224.69
  pour cut-out: 635.93,125.54 633.37,122.98 629.24,122.98 628.11,124.12 628.11,160.22 596.01,192.32 596.01,195.51 595.94,195.8 606.21,206.07 624.56,206.07 628.11,202.52 628.11,184.17 704.66,107.62 704.66,104.68 700.39,100.41 675.16,100.41 650.04,125.54
Mid Layer 2:
  region net GND: 844,353 ccw(c845.93,354.93) 845.93,352.2 861.93,352.2 cw(c862.1,340.86) 870,349 870.59,348.41 cw(c864.18,342) 873.24,342 881.9,342 ccw(c880.69,343.21) 882.4,343.21 882.4,352.68 ccw(c870.75,352.68) 878.99,360.91 875.1,364.8 ccw(c870.75,360.46) 870.75,366.6 843,366.6 843,355.41 ccw(c846.42,355.41)
  pour cut-out: 230.41,140.39 cw(c235.22,135.59) 235.22,142.38 273.12,142.38 cw(c273.08,132.97) 279.76,139.6 cw(c268.5,128.4) 284.38,128.4 284.38,87.1 cw(c278.69,87.03) 282.76,83.06 cw(c279.1,86.08) 282.46,82.72 cw(c267.73,97.45) 267.73,76.62 238.36,76.62 cw(c238.36,87.49) 230.67,79.81 228.06,82.42 cw(c241.82,96.19) 222.36,96.19 222.36,127.07 cw(c237.29,127.07) 226.73,137.62 227.19,138.09 cw(c235.73,129.56)
  pour cut-out: 222.7,418.18 222.73,422.98 258.73,422.98 cw(c258.71,404.89) 271.52,417.66 cw(c268.93,411.41) 273.73,416.18 cw(c273.11,415.52) 273.78,416.13 cw(c265.01,407.47) 277.33,407.39 277.33,176.18 232.93,176.18 232.93,370.46 ccw(c227.82,370.46) 231.43,374.08 ccw(c226.36,369.02) 226.36,376.18 222.7,376.18
  pour cut-out: 579.61,589.27 523,589.28 523,577.46 539.36,577.46 542.25,574.57 542.25,565.01 579.61,565.01
  pour cut-out: 848,346.18 848,702.18 895,702.18 895,346.18
  pour cut-out: 652.69,701.99 898.05,701.99 898.05,654.99 652.69,654.99
  pour cut-out: 201,701.99 405.71,701.99 405.71,654.99 201,654.99
  pour cut-out: 285.73,134.68 277.33,134.68 277.13,134.88 276.93,134.68 276.93,125.88
  pour cut-out: 277.43,183.98 277.43,175.58 277.23,175.38 277.43,175.18 286.23,175.18
  pour cut-out: 308.15,135.31 233.29,135.31 233.29,177.43 308.15,177.43
  pour cut-out: 195.82,418.18 278.73,418.18 278.73,374.18 195.82,374.18
  pour cut-out: 646.91,266.42 726.83,346.34 811.99,346.34 823.98,334.35 823.98,191.42 770.36,137.8 667.18,137.8 667.18,129.92 778.13,129.92 833.59,185.39 833.59,344.45 823.48,354.56 721.11,354.56 642.07,275.51 606.3,275.51 606.3,266.42
Mid-Layer 3:
  pour cut-out: 230.41,140.39 cw(c235.22,135.59) 235.22,142.38 273.12,142.38 cw(c273.08,132.97) 279.76,139.6 cw(c268.5,128.4) 284.38,128.4 284.38,87.1 cw(c278.69,87.03) 282.76,83.06 cw(c279.1,86.08) 282.46,82.72 cw(c267.73,97.45) 267.73,76.62 238.36,76.62 cw(c238.36,87.49) 230.67,79.81 228.06,82.42 cw(c241.82,96.19) 222.36,96.19 222.36,127.07 cw(c237.29,127.07) 226.73,137.62 227.19,138.09 cw(c235.73,129.56)
  pour cut-out: 222.7,418.18 222.73,422.98 258.73,422.98 cw(c258.71,404.89) 271.52,417.66 cw(c268.93,411.42) 273.73,416.18 cw(c273.24,415.66) 273.78,416.13 cw(c265.01,407.47) 277.33,407.39 277.33,172.26 232.93,172.26 232.93,370.46 ccw(c227.82,370.46) 231.43,374.08 ccw(c226.36,369.02) 226.36,376.18 222.7,376.18
  pour cut-out: 848,347.18 848,702.18 895,702.18 895,347.18
  pour cut-out: 652.69,701.99 898.05,701.99 898.05,654.99 652.69,654.99
  pour cut-out: 202,701.99 405.71,701.99 405.71,654.99 202,654.99
  pour cut-out: 288.53,135.58 280.13,135.58 279.93,135.78 279.73,135.58 279.73,126.78
  pour cut-out: 278.73,180.38 278.73,171.98 278.53,171.78 278.73,171.58 287.53,171.58
  pour cut-out: 296.33,135.18 233.13,135.18 233.13,177.31 296.33,177.31
  pour cut-out: 195.82,418.18 278.73,418.18 278.73,376.18 195.82,376.18
Mid-Layer 4:
  pour cut-out: 222.7,416.39 222.73,421.19 258.73,421.19 cw(c258.71,403.09) 271.52,415.87 cw(c268.93,409.62) 273.73,414.38 cw(c273.11,413.73) 273.78,414.33 cw(c265.01,405.68) 277.33,405.59 277.33,173.42 232.93,173.42 232.93,368.66 ccw(c227.82,368.67) 231.43,372.29 ccw(c226.36,367.22) 226.36,374.39 222.7,374.39
  pour cut-out: 230.41,140.39 cw(c235.22,135.59) 235.22,142.38 273.12,142.38 cw(c273.08,132.97) 279.76,139.6 cw(c268.5,128.4) 284.38,128.4 284.38,87.1 cw(c278.69,87.03) 282.76,83.06 cw(c279.1,86.08) 282.46,82.72 cw(c267.73,97.45) 267.73,76.62 238.36,76.62 cw(c238.36,87.49) 230.67,79.81 228.06,82.42 cw(c241.82,96.19) 222.36,96.19 222.36,127.07 cw(c237.29,127.07) 226.73,137.62 227.19,138.09 cw(c235.73,129.56)
  pour cut-out: 848,347.18 848,702.18 895,702.18 895,347.18
  pour cut-out: 202,701.99 405.71,701.99 405.71,654.99 202,654.99
  pour cut-out: 653.02,701.99 898.05,701.99 898.05,654.99 653.02,654.99
  pour cut-out: 289.61,135.58 281.21,135.58 281.01,135.78 280.81,135.58 280.81,126.78
  pour cut-out: 278.73,180.66 278.73,172.26 278.53,172.06 278.73,171.86 287.53,171.86
  pour cut-out: 295.99,134.62 232.78,134.62 232.78,176.75 295.99,176.75
  pour cut-out: 195.82,418.18 278.73,418.18 278.73,376.18 195.82,376.18
Bottom Layer:
  pour cut-out: 205,701.99 405.71,701.99 405.71,654.99 205,654.99
  pour cut-out: 653.02,701.99 898.05,701.99 898.05,654.99 653.02,654.99
  pour cut-out: 848,347.18 848,702.18 895,702.18 895,347.18
Multi-Layer:
  pour cut-out: 175.73,-28.82 175.73,79.02 206.52,79.02 206.52,707.56 0,707.55 0,-28.82

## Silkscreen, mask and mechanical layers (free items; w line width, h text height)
Top Overlay:
  lines w4.92: 434.22,180.5 450.35,180.5 ; 450.35,181.22 450.35,198.8
  text "NORDIC" at 608.73,424.94 h60
Bottom Overlay:
  text "VnRF" at 290.3,647.49 h23 r90
  text "GND" at 240.34,644.54 h23 r90
  text "VBAT" at 820.09,405.74 h23
  text "GND" at 817.82,366.91 h23
Top Solder:
  region: 415.24,639.05 415.24,658.34 297,658.34 297,639.05
  region: 578.73,9.35 578.73,37.11 558,37.11 558,9.35
  rectangle: 828.17,451 850.26,483
  region: 690.9,11.35 690.9,39.11 647.79,39.11 647.79,11.35
  region: 661.8,635.68 661.8,660.28 639.03,660.28 639.03,635.68
  rectangle: 276.32,191.31 297.27,648
  region: 744.28,638.39 744.28,659 701.34,659 701.34,638.39
  rectangle: 827.21,619.09 851.21,656.52
  region: 810,11.35 810,39.11 740,39.11 740,11.35
  rectangle: 825.33,35.19 853.09,98.95
  region: 435,33 435.06,33.06 448.94,33.06 451.94,30.06 471.09,30.06 473.9,32.88 500,32.88 500,9 435,9 435,32.88
Board Outline:
  the board outline again, w6
Top Assembly:
  lines w4.3: 622.92,249.47 457.16,249.47 457.16,98.67 609.2,98.67 623.45,112.93 623.45,248.93
  text "U1" at 533.73,199.08 h12
  text "A1" at 619.32,129.02 h12 r180
Top Impedance Info:
  rectangle: 206.53,383.67 230.03,412.67
  rectangle: 241.38,304.17 270.38,370.23
  rectangle: 241.38,206.39 270.38,288.42
  region: 228.17,412.67 248.26,412.67 cw(c248.27,386.58) 266.71,405.03 cw(c266.54,404.84) 266.73,405.01 cw(c257.97,396.25) 270.36,396.25 270.36,377.4 270.37,370.02 241.38,370.02 241.38,378.53 ccw(c236.05,378.53) 239.82,382.3 ccw(c236.51,378.99) 236.51,383.67 228.17,383.67
  lines w4.5: 417.8,201.9 417.8,211.13 450.07,243.41 450.69,243.41 ; 426.4,218 426.4,200.6 436.3,190.7 436.3,173.3 ; 450.69,217.41 450.69,269.41 ; 450.69,269.41 451.69,269.41 458.69,262.41 443.69,262.41 450.69,269.41
  lines w4.92: 176.88,242.18 180.6,238.46 180.84,238.46 180.6,238.22 173.05,238.22 172.87,238.4 173.34,238.4 177,242.06 177,242.53 177.18,242.35 177.18,226.18 232.73,226.18 ; 324.05,421.99 350.18,421.99 344.53,427.64 344.53,416.46 349.95,421.88
  lines w5.75: 466.89,207.08 cw(c463.01,170.65) 475.42,205.12 cw(c463.01,170.65) 478.7,203.76 482.1,202.14 cw(c477.42,192.26) 484.12,200.9 484.16,200.88 490.52,195.94 ccw(c501.31,206.72) 493.54,193.6 ccw(c501.31,206.72) 497.91,191.86 ccw(c501.31,206.72) 501.31,191.47 504.99,191.47 ; 491.21,162.43 ccw(c481.34,162.43) 488.34,169.38 ; 487.94,169.78 ccw(c474.36,156.2) 474.41,175.4 cw(c474.36,156.2) 487.94,169.78 ; 487.94,169.78 488.32,169.41 ; 487.94,169.78 488.32,169.41 ; 488.34,169.38 ccw(c481.34,162.43) 488.32,169.41 ; 488.34,169.38 ccw(c481.34,162.43) 488.32,169.41
  lines w5.76: 360.42,137.4 363.03,137.4 ; 363.03,137.18 388.08,137.18 ccw(c388.08,183.75) 421.01,150.82 428.02,157.83 cw(c470.36,115.49) 470.36,175.37 474.64,175.37 cw(c474.6,156.17) 488.18,169.75 488.55,169.37 cw(c481.57,162.39) 488.57,169.35 cw(c481.57,162.39) 491.44,162.39 ; 363.02,176.53 410.13,176.53 ccw(c410.13,185.38) 416.39,179.12 ccw(c410.34,185.17) 418.9,185.17 418.9,192.1 ; 435.07,207.46 463.14,207.46 466.89,207.08 ; 466.89,207.08 466.89,207.08
  lines w12: 336.08,557.85 326.32,557.85 ccw(c326.32,548.5) 319.7,555.11 ccw(c341.43,533.39) 310.7,533.39 310.7,256.16 ccw(c342.38,256.16) 319.98,233.76 ccw(c347.4,261.17) 347.4,222.4 391.24,222.4 395.54,220.62 cw(c395.54,218.95) 396.72,220.14 403.13,213.72 403.13,212.37 403.13,212.2
  lines w29: 255.88,187 255.88,216.71
  text "50 ohms co-planar / reference mid layer2" at 353,400 h10
  text "50 ohms Microstrip / reference Mid layer1" at 380.73,274.18 h10
  text "50 ohms co-planar / reference  Bottom" at 78.73,250.18 h10
  text "Note: Total Stackup height is 1mm only." at -77,-219.34 h50

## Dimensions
890.45,692.95 to 890.45,0 on Dimensions
0,0 to 890.45,0 on Dimensions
